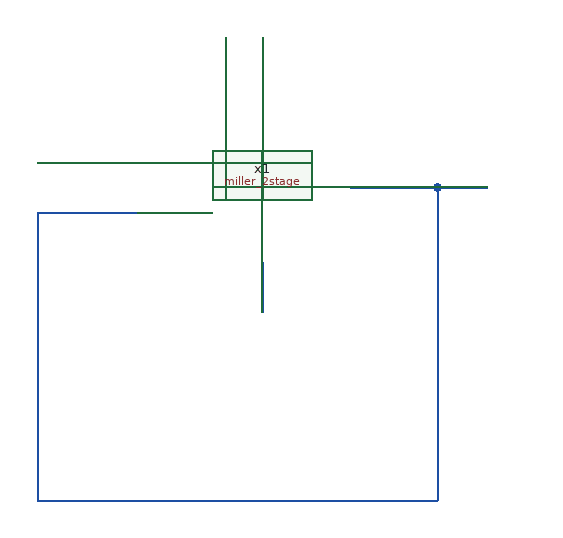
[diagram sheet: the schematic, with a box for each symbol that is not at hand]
v {xschem version=3.1.0 file_version=1.2
}
G {}
K {}
V {}
S {}
E {}
N 1510 -1180 1590 -1180 {
lab=#net1}
N 1510 -1140 1590 -1140 {
lab=#net2}
N 1690 -1280 1690 -1240 {
lab=#net3}
N 1510 -910 1620 -910 {
lab=#net2}
N 1510 -1140 1510 -910 {
lab=#net2}
N 1680 -910 1830 -910 {
lab=#net4}
N 1830 -1160 1830 -910 {
lab=#net4}
N 1760 -1160 1830 -1160 {
lab=#net4}
N 1830 -1160 1870 -1160 {
lab=#net4}
N 1690 -1100 1690 -1060 {
lab=#net5}
N 1660 -1280 1660 -1240 {
lab=#net6}
N 1620 -910 1680 -910 {}
C {ip_block/opamp/miller_2stage/miller_2stage.sym} 1690 -1160 0 0 {name=x1}
